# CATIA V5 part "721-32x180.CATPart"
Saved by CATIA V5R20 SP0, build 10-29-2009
Part number: 721-32x180
Definition: NONE
Nomenclature: 721-32x180
Source: Unknown
Description: 721-32x180
Bounding box of the stored display mesh (mm): x -80 to 100, y -30 to 30, z -30 to 30
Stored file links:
  C:\Users\Utente\Desktop\IO LAVORO\3D X SITO CF\X SITO\721\721-32x180.CATPart

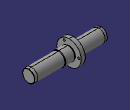
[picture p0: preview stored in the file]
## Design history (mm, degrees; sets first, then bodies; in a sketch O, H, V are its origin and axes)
Body1 "721-32x180" (main body)
  Solid1: solid without history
